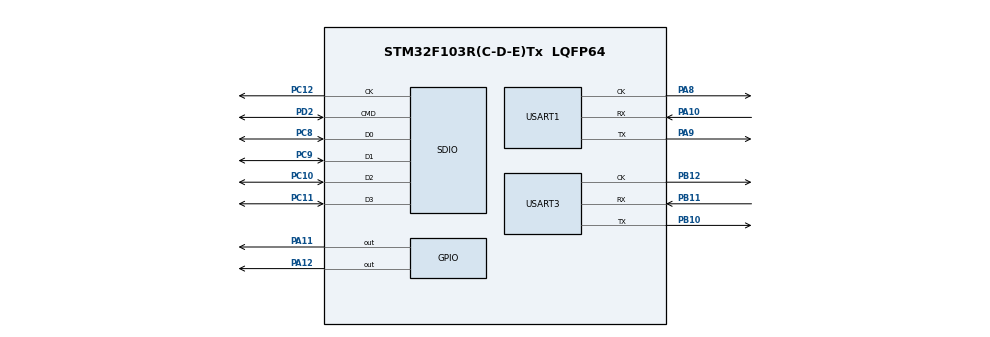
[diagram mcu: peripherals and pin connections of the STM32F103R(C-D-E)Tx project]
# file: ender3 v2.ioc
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Mcu.Family=STM32F1
Mcu.Name=STM32F103R(C-D-E)Tx
Mcu.Package=LQFP64
NVIC.PriorityGroup=NVIC_PRIORITYGROUP_4
PA10.Mode=Synchronous
PA10.Signal=USART1_RX
PA11.Signal=GPIO_Output
PA12.Signal=GPIO_Output
PA8.Mode=Synchronous
PA8.Signal=USART1_CK
PA9.Mode=Synchronous
PA9.Signal=USART1_TX
PB10.Mode=Synchronous
PB10.Signal=USART3_TX
PB11.Mode=Synchronous
PB11.Signal=USART3_RX
PB12.Mode=Synchronous
PB12.Signal=USART3_CK
PC10.Mode=SD_4_bits_Wide_bus
PC10.Signal=SDIO_D2
PC11.Mode=SD_4_bits_Wide_bus
PC11.Signal=SDIO_D3
PC12.Mode=SD_4_bits_Wide_bus
PC12.Signal=SDIO_CK
PC8.Mode=SD_4_bits_Wide_bus
PC8.Signal=SDIO_D0
PC9.Mode=SD_4_bits_Wide_bus
PC9.Signal=SDIO_D1
PD0-OSC_IN.Mode=HSE-External-Oscillator
PD0-OSC_IN.Signal=RCC_OSC_IN
PD1-OSC_OUT.Mode=HSE-External-Oscillator
PD1-OSC_OUT.Signal=RCC_OSC_OUT
PD2.Mode=SD_4_bits_Wide_bus
PD2.Signal=SDIO_CMD
ProjectManager.HeapSize=0x200
ProjectManager.StackSize=0x400
ProjectManager.TargetToolchain=MDK-ARM V5.32
RCC.APB1Freq_Value=8000000
RCC.APB2Freq_Value=8000000
USART1.VirtualMode=VM_SYNC
USART3.VirtualMode=VM_SYNC
VP_FATFS_VS_SDIO.Mode=SDIO
VP_SYS_VS_ND.Mode=No_Debug
board=custom

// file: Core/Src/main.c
/* USER CODE BEGIN Header */
/**
  ******************************************************************************
  * @file           : main.c
  * @brief          : Main program body
  ******************************************************************************
  * @attention
  *
  * Copyright (c) 2026 STMicroelectronics.
  * All rights reserved.
  *
  * This software is licensed under terms that can be found in the LICENSE file
  * in the root directory of this software component.
  * If no LICENSE file comes with this software, it is provided AS-IS.
  *
  ******************************************************************************
  */
/* USER CODE END Header */
#include "main.h"
#include "fatfs.h"
#include "sdio.h"
#include "usart.h"
#include "gpio.h"

/* USER CODE BEGIN Includes */
#include "app_bl.h"
#include "Banux.h"
#include "driver_init.h"
#include "shell_io_uart.h"
/* USER CODE END Includes */

void SystemClock_Config(void);

int main(void)
{

  /* MCU Configuration--------------------------------------------------------*/

  /* Reset of all peripherals, Initializes the Flash interface and the Systick. */
  HAL_Init();

  /* USER CODE BEGIN Init */

  /* APP 链接在 0x08008000（Bootloader 之后），必须把向量表偏移到应用区，
   * 否则中断向量仍指向 Bootloader 的 0x08000000，任何中断都会跑飞。 */
#define APP_VECTOR_TABLE_ADDR   0x08008000u
  SCB->VTOR = APP_VECTOR_TABLE_ADDR;

  /* 恢复全局中断：BL 跳转前调用 __disable_irq()（PRIMASK=1），软件跳转不清 PRIMASK，
   * 若不恢复，所有中断（含 USART1/3 RX）保持屏蔽，UART 收不到任何数据。 */
  __enable_irq();

  /* USER CODE END Init */

  /* Configure the system clock */
  SystemClock_Config();

  /* Initialize all configured peripherals */
  MX_GPIO_Init();
  MX_SDIO_SD_Init();
  MX_USART3_Init();
  MX_USART1_Init();
  /* USER CODE BEGIN 2 */

  /* 启动日志：与 Bootloader 同一条 UART 链路输出 */
  app_log("\r\n");
  app_log("========== APP ==========\r\n");
  app_log_u32("clk: SYSCLK=", HAL_RCC_GetSysClockFreq());
  app_log("UPGRADE: listening ENTER_BOOT (UART1 @2000000 / UART3 @115200) [diag]\r\n");

  {
    const BanuxConfig_t banuxConfig = {
      app_log,
      ShellIO_UartAll_Get(),
      MX_FATFS_Init,
      BanuxDriver_RegisterAll,
      app_bl_init,
      app_bl_poll
    };
    if (Banux_Init(&banuxConfig) != 0) {
      app_log("UPGRADE: Banux_Init FAILED\r\n");
    }
  }
  app_log("UPGRADE: entering main loop\r\n");

  /* USER CODE END 2 */

  /* Infinite loop */
  while (1)
  {

    /* USER CODE BEGIN 3 */
    Banux_Process();
  }
  /* USER CODE END 3 */
}

void SystemClock_Config(void)
{
  RCC_OscInitTypeDef RCC_OscInitStruct = {0};
  RCC_ClkInitTypeDef RCC_ClkInitStruct = {0};

  /** 与 Bootloader 一致的 64MHz 系统时钟（HSE 8MHz x PLL x8），
   *  USART1=APB2/1=64MHz、USART3=APB1/2=32MHz，保证 2M baud 精确。
   */
  RCC_OscInitStruct.OscillatorType = RCC_OSCILLATORTYPE_HSE;
  RCC_OscInitStruct.HSEState = RCC_HSE_ON;
  RCC_OscInitStruct.HSEPredivValue = RCC_HSE_PREDIV_DIV1;
  RCC_OscInitStruct.HSIState = RCC_HSI_ON;
  RCC_OscInitStruct.PLL.PLLState = RCC_PLL_ON;
  RCC_OscInitStruct.PLL.PLLSource = RCC_PLLSOURCE_HSE;
  RCC_OscInitStruct.PLL.PLLMUL = RCC_PLL_MUL8;
  if (HAL_RCC_OscConfig(&RCC_OscInitStruct) != HAL_OK)
  {
    Error_Handler();
  }

  /** Initializes the CPU, AHB and APB buses clocks
  */
  RCC_ClkInitStruct.ClockType = RCC_CLOCKTYPE_HCLK|RCC_CLOCKTYPE_SYSCLK
                              |RCC_CLOCKTYPE_PCLK1|RCC_CLOCKTYPE_PCLK2;
  RCC_ClkInitStruct.SYSCLKSource = RCC_SYSCLKSOURCE_PLLCLK;
  RCC_ClkInitStruct.AHBCLKDivider = RCC_SYSCLK_DIV1;
  RCC_ClkInitStruct.APB1CLKDivider = RCC_HCLK_DIV2;
  RCC_ClkInitStruct.APB2CLKDivider = RCC_HCLK_DIV1;

  if (HAL_RCC_ClockConfig(&RCC_ClkInitStruct, FLASH_LATENCY_2) != HAL_OK)
  {
    Error_Handler();
  }
}

void Error_Handler(void)
{
  __disable_irq();
  while (1)
  {
  }
}
